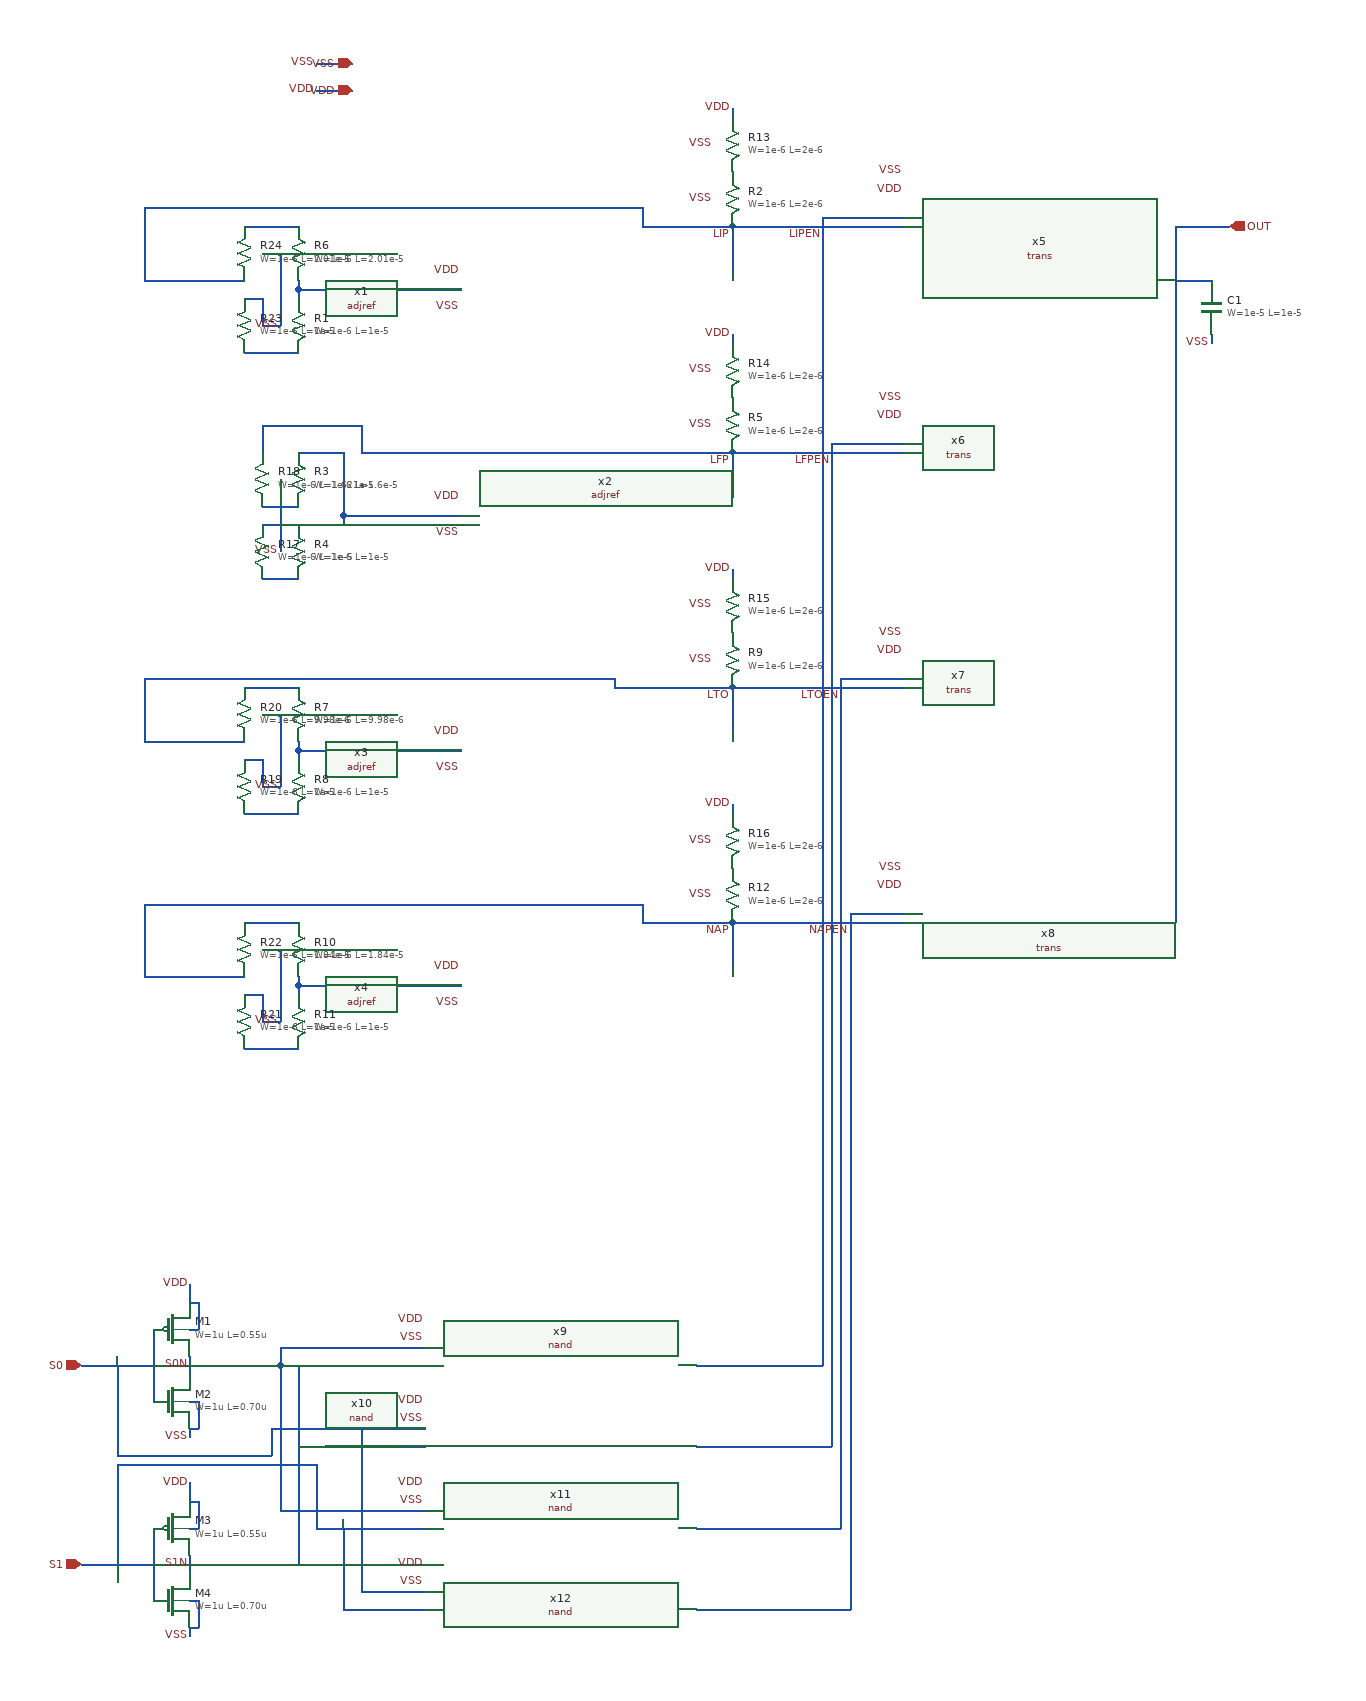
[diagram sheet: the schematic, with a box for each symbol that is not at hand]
v {xschem version=3.4.8RC file_version=1.3}
G {}
K {}
V {}
S {}
F {}
E {}
N -250 -250 -210 -250 {lab=VSS}
N -250 -220 -210 -220 {lab=VDD}
N -270 -0 -90 0 {lab=#net1}
N -270 -10 -270 -0 {lab=#net1}
N -270 0 -270 10 {lab=#net1}
N -290 70 -270 70 {lab=#net2}
N 210 180 210 230 {lab=LFP}
N -270 510 -90 510 {lab=#net3}
N -270 500 -270 510 {lab=#net3}
N -270 510 -270 520 {lab=#net3}
N -290 580 -270 580 {lab=#net4}
N 210 440 210 490 {lab=LTO}
N -270 770 -90 770 {lab=#net5}
N -270 760 -270 770 {lab=#net5}
N -270 770 -270 780 {lab=#net5}
N -290 840 -270 840 {lab=#net6}
N 210 700 210 750 {lab=NAP}
N 210 -70 400 -70 {lab=LIP}
N 210 -70 210 -20 {lab=LIP}
N 210 180 400 180 {lab=LFP}
N 210 440 400 440 {lab=LTO}
N 700 -70 760 -70 {lab=OUT}
N 700 -70 700 700 {lab=OUT}
N -390 1230 -380 1230 {lab=VSS}
N -380 1230 -380 1260 {lab=VSS}
N -390 1260 -380 1260 {lab=VSS}
N -390 1260 -390 1270 {lab=VSS}
N -390 1150 -380 1150 {lab=VDD}
N -380 1120 -380 1150 {lab=VDD}
N -390 1120 -380 1120 {lab=VDD}
N -390 1100 -390 1120 {lab=VDD}
N -390 1180 -390 1200 {lab=S0N}
N -430 1150 -430 1230 {lab=S0}
N -390 1450 -380 1450 {lab=VSS}
N -380 1450 -380 1480 {lab=VSS}
N -390 1480 -380 1480 {lab=VSS}
N -390 1480 -390 1490 {lab=VSS}
N -390 1370 -380 1370 {lab=VDD}
N -380 1340 -380 1370 {lab=VDD}
N -390 1340 -380 1340 {lab=VDD}
N -390 1320 -390 1340 {lab=VDD}
N -390 1400 -390 1420 {lab=S1N}
N -430 1370 -430 1450 {lab=S1}
N -510 1190 -430 1190 {lab=S0}
N -510 1410 -430 1410 {lab=S1}
N 700 -10 740 -10 {lab=OUT}
N 740 50 740 60 {lab=VSS}
N -290 1170 -130 1170 {lab=S0N}
N -290 1170 -290 1190 {lab=S0N}
N -390 1190 -290 1190 {lab=S0N}
N -270 1190 -130 1190 {lab=S1N}
N -270 1190 -270 1410 {lab=S1N}
N -390 1410 -270 1410 {lab=S1N}
N -300 1260 -130 1260 {lab=S0}
N -300 1260 -300 1290 {lab=S0}
N -470 1290 -300 1290 {lab=S0}
N -470 1190 -470 1290 {lab=S0}
N -270 1280 -130 1280 {lab=S1N}
N -250 1370 -130 1370 {lab=S1}
N -250 1300 -250 1370 {lab=S1}
N -470 1300 -250 1300 {lab=S1}
N -470 1300 -470 1410 {lab=S1}
N -290 1350 -130 1350 {lab=S0N}
N -290 1190 -290 1350 {lab=S0N}
N -200 1440 -130 1440 {lab=S0}
N -200 1260 -200 1440 {lab=S0}
N -220 1460 -130 1460 {lab=S1}
N -220 1370 -220 1460 {lab=S1}
N 310 -80 400 -80 {lab=LIPEN}
N 310 -80 310 1190 {lab=LIPEN}
N 170 1190 310 1190 {lab=LIPEN}
N 320 170 400 170 {lab=LFPEN}
N 320 170 320 1280 {lab=LFPEN}
N 170 1280 320 1280 {lab=LFPEN}
N 330 430 400 430 {lab=LTOEN}
N 330 430 330 1370 {lab=LTOEN}
N 170 1370 330 1370 {lab=LTOEN}
N 340 690 400 690 {lab=NAPEN}
N 340 690 340 1460 {lab=NAPEN}
N 170 1460 340 1460 {lab=NAPEN}
N 210 700 400 700 {lab=NAP}
N 210 50 210 60 {lab=VDD}
N 210 -200 210 -190 {lab=VDD}
N 210 310 210 320 {lab=VDD}
N 210 570 210 580 {lab=VDD}
N -310 320 -270 320 {lab=#net7}
N -290 210 -290 290 {lab=VSS}
N -200 180 210 180 {lab=LFP}
N -200 150 -200 180 {lab=LFP}
N -310 150 -200 150 {lab=LFP}
N -310 150 -310 180 {lab=LFP}
N -310 240 -270 240 {lab=#net8}
N -270 180 -220 180 {lab=#net9}
N -220 180 -220 250 {lab=#net9}
N -220 250 -90 250 {lab=#net9}
N -310 260 -290 260 {lab=VSS}
N -270 260 -220 260 {lab=#net9}
N -220 250 -220 260 {lab=#net9}
N -330 520 -310 520 {lab=VSS}
N -310 520 -310 550 {lab=VSS}
N -310 550 -290 550 {lab=VSS}
N -330 580 -290 580 {lab=#net4}
N -290 470 -290 550 {lab=VSS}
N -310 470 -290 470 {lab=VSS}
N -330 440 -270 440 {lab=#net10}
N -440 500 -330 500 {lab=LTO}
N -440 430 -440 500 {lab=LTO}
N -440 430 80 430 {lab=LTO}
N 80 430 80 440 {lab=LTO}
N 80 440 210 440 {lab=LTO}
N -310 810 -290 810 {lab=VSS}
N -330 840 -290 840 {lab=#net6}
N -290 730 -290 810 {lab=VSS}
N -310 730 -290 730 {lab=VSS}
N -330 780 -310 780 {lab=VSS}
N -310 780 -310 810 {lab=VSS}
N -330 700 -270 700 {lab=#net11}
N -440 760 -330 760 {lab=NAP}
N -440 680 -440 760 {lab=NAP}
N -440 680 110 680 {lab=NAP}
N 110 680 110 700 {lab=NAP}
N 110 700 210 700 {lab=NAP}
N -330 70 -290 70 {lab=#net2}
N -330 10 -310 10 {lab=VSS}
N -310 10 -310 40 {lab=VSS}
N -310 40 -290 40 {lab=VSS}
N -290 -40 -290 40 {lab=VSS}
N -310 -40 -290 -40 {lab=VSS}
N -330 -70 -270 -70 {lab=#net12}
N -440 -10 -330 -10 {lab=LIP}
N -440 -90 -440 -10 {lab=LIP}
N -440 -90 110 -90 {lab=LIP}
N 110 -90 110 -70 {lab=LIP}
N 110 -70 210 -70 {lab=LIP}
C {adjref.sym} 60 0 0 0 {name=x1}
C {symbols/ppolyf_u_1k_6p0.sym} -270 -40 0 0 {name=R6
W=1e-6
L=2.01e-5
model=ppolyf_u_1k
spiceprefix=X
m=1}
C {lab_pin.sym} -250 -250 0 0 {name=p26 sig_type=std_logic lab=VSS}
C {iopin.sym} -210 -250 0 0 {name=p27 lab=VSS}
C {lab_pin.sym} -250 -220 0 0 {name=p30 sig_type=std_logic lab=VDD}
C {iopin.sym} -210 -220 0 0 {name=p31 lab=VDD}
C {lab_pin.sym} -90 20 0 0 {name=p1 sig_type=std_logic lab=VSS}
C {lab_pin.sym} -90 -20 0 0 {name=p2 sig_type=std_logic lab=VDD}
C {symbols/ppolyf_u_1k_6p0.sym} -270 40 0 0 {name=R1
W=1e-6
L=1e-5
model=ppolyf_u_1k
spiceprefix=X
m=1}
C {lab_pin.sym} -290 40 1 0 {name=p3 sig_type=std_logic lab=VSS}
C {symbols/ppolyf_u_1k_6p0.sym} 210 -100 0 0 {name=R2
W=1e-6
L=2e-6
model=ppolyf_u_1k
spiceprefix=X
m=1}
C {lab_pin.sym} 190 -100 0 0 {name=p4 sig_type=std_logic lab=VSS}
C {adjref.sym} 60 250 0 0 {name=x2}
C {symbols/ppolyf_u_1k_6p0.sym} -270 210 0 0 {name=R3
W=1e-6
L=1.6e-5
model=ppolyf_u_1k
spiceprefix=X
m=1}
C {lab_pin.sym} -90 270 0 0 {name=p9 sig_type=std_logic lab=VSS}
C {lab_pin.sym} -90 230 0 0 {name=p10 sig_type=std_logic lab=VDD}
C {symbols/ppolyf_u_1k_6p0.sym} -270 290 0 0 {name=R4
W=1e-6
L=1e-5
model=ppolyf_u_1k
spiceprefix=X
m=1}
C {lab_pin.sym} -290 290 1 0 {name=p11 sig_type=std_logic lab=VSS}
C {symbols/ppolyf_u_1k_6p0.sym} 210 150 0 0 {name=R5
W=1e-6
L=2e-6
model=ppolyf_u_1k
spiceprefix=X
m=1}
C {lab_pin.sym} 190 150 0 0 {name=p12 sig_type=std_logic lab=VSS}
C {lab_pin.sym} 210 -60 0 0 {name=p6 sig_type=std_logic lab=LIP}
C {lab_pin.sym} 210 190 0 0 {name=p14 sig_type=std_logic lab=LFP}
C {adjref.sym} 60 510 0 0 {name=x3}
C {symbols/ppolyf_u_1k_6p0.sym} -270 470 0 0 {name=R7
W=1e-6
L=9.98e-6
model=ppolyf_u_1k
spiceprefix=X
m=1}
C {lab_pin.sym} -90 530 0 0 {name=p16 sig_type=std_logic lab=VSS}
C {lab_pin.sym} -90 490 0 0 {name=p17 sig_type=std_logic lab=VDD}
C {symbols/ppolyf_u_1k_6p0.sym} -270 550 0 0 {name=R8
W=1e-6
L=1e-5
model=ppolyf_u_1k
spiceprefix=X
m=1}
C {lab_pin.sym} -290 550 1 0 {name=p18 sig_type=std_logic lab=VSS}
C {symbols/ppolyf_u_1k_6p0.sym} 210 410 0 0 {name=R9
W=1e-6
L=2e-6
model=ppolyf_u_1k
spiceprefix=X
m=1}
C {lab_pin.sym} 190 410 0 0 {name=p19 sig_type=std_logic lab=VSS}
C {lab_pin.sym} 210 450 0 0 {name=p21 sig_type=std_logic lab=LTO}
C {adjref.sym} 60 770 0 0 {name=x4}
C {symbols/ppolyf_u_1k_6p0.sym} -270 730 0 0 {name=R10
W=1e-6
L=1.84e-5
model=ppolyf_u_1k
spiceprefix=X
m=1}
C {lab_pin.sym} -90 790 0 0 {name=p23 sig_type=std_logic lab=VSS}
C {lab_pin.sym} -90 750 0 0 {name=p24 sig_type=std_logic lab=VDD}
C {symbols/ppolyf_u_1k_6p0.sym} -270 810 0 0 {name=R11
W=1e-6
L=1e-5
model=ppolyf_u_1k
spiceprefix=X
m=1}
C {lab_pin.sym} -290 810 1 0 {name=p25 sig_type=std_logic lab=VSS}
C {symbols/ppolyf_u_1k_6p0.sym} 210 670 0 0 {name=R12
W=1e-6
L=2e-6
model=ppolyf_u_1k
spiceprefix=X
m=1}
C {lab_pin.sym} 190 670 0 0 {name=p28 sig_type=std_logic lab=VSS}
C {lab_pin.sym} 210 710 0 0 {name=p32 sig_type=std_logic lab=NAP}
C {trans.sym} 550 -100 0 0 {name=x5}
C {lab_pin.sym} 400 -130 0 0 {name=p33 sig_type=std_logic lab=VSS}
C {lab_pin.sym} 400 -110 0 0 {name=p34 sig_type=std_logic lab=VDD}
C {trans.sym} 550 150 0 0 {name=x6}
C {lab_pin.sym} 400 120 0 0 {name=p35 sig_type=std_logic lab=VSS}
C {lab_pin.sym} 400 140 0 0 {name=p36 sig_type=std_logic lab=VDD}
C {trans.sym} 550 410 0 0 {name=x7}
C {lab_pin.sym} 400 380 0 0 {name=p37 sig_type=std_logic lab=VSS}
C {lab_pin.sym} 400 400 0 0 {name=p38 sig_type=std_logic lab=VDD}
C {trans.sym} 550 670 0 0 {name=x8}
C {lab_pin.sym} 400 640 0 0 {name=p39 sig_type=std_logic lab=VSS}
C {lab_pin.sym} 400 660 0 0 {name=p40 sig_type=std_logic lab=VDD}
C {opin.sym} 760 -70 0 0 {name=p41 lab=OUT}
C {symbols/pfet_06v0.sym} -410 1150 0 0 {name=M1
L=0.55u
W=1u
nf=1
m=1
ad="'int((nf+1)/2) * W/nf * 0.18u'"
pd="'2*int((nf+1)/2) * (W/nf + 0.18u)'"
as="'int((nf+2)/2) * W/nf * 0.18u'"
ps="'2*int((nf+2)/2) * (W/nf + 0.18u)'"
nrd="'0.18u / W'" nrs="'0.18u / W'"
sa=0 sb=0 sd=0
model=pfet_06v0
spiceprefix=X
}
C {symbols/nfet_06v0.sym} -410 1230 0 0 {name=M2
L=0.70u
W=1u
nf=1
m=1
ad="'int((nf+1)/2) * W/nf * 0.18u'"
pd="'2*int((nf+1)/2) * (W/nf + 0.18u)'"
as="'int((nf+2)/2) * W/nf * 0.18u'"
ps="'2*int((nf+2)/2) * (W/nf + 0.18u)'"
nrd="'0.18u / W'" nrs="'0.18u / W'"
sa=0 sb=0 sd=0
model=nfet_06v0
spiceprefix=X
}
C {lab_pin.sym} -390 1270 0 0 {name=p42 sig_type=std_logic lab=VSS}
C {lab_pin.sym} -390 1100 0 0 {name=p43 sig_type=std_logic lab=VDD}
C {symbols/pfet_06v0.sym} -410 1370 0 0 {name=M3
L=0.55u
W=1u
nf=1
m=1
ad="'int((nf+1)/2) * W/nf * 0.18u'"
pd="'2*int((nf+1)/2) * (W/nf + 0.18u)'"
as="'int((nf+2)/2) * W/nf * 0.18u'"
ps="'2*int((nf+2)/2) * (W/nf + 0.18u)'"
nrd="'0.18u / W'" nrs="'0.18u / W'"
sa=0 sb=0 sd=0
model=pfet_06v0
spiceprefix=X
}
C {symbols/nfet_06v0.sym} -410 1450 0 0 {name=M4
L=0.70u
W=1u
nf=1
m=1
ad="'int((nf+1)/2) * W/nf * 0.18u'"
pd="'2*int((nf+1)/2) * (W/nf + 0.18u)'"
as="'int((nf+2)/2) * W/nf * 0.18u'"
ps="'2*int((nf+2)/2) * (W/nf + 0.18u)'"
nrd="'0.18u / W'" nrs="'0.18u / W'"
sa=0 sb=0 sd=0
model=nfet_06v0
spiceprefix=X
}
C {lab_pin.sym} -390 1490 0 0 {name=p44 sig_type=std_logic lab=VSS}
C {lab_pin.sym} -390 1320 0 0 {name=p45 sig_type=std_logic lab=VDD}
C {ipin.sym} -510 1190 0 0 {name=p46 lab=S0}
C {ipin.sym} -510 1410 0 0 {name=p47 lab=S1}
C {nand.sym} 20 1170 0 0 {name=x9}
C {nand.sym} 20 1260 0 0 {name=x10}
C {nand.sym} 20 1350 0 0 {name=x11}
C {nand.sym} 20 1440 0 0 {name=x12}
C {lab_pin.sym} 740 60 3 0 {name=p48 sig_type=std_logic lab=VSS}
C {lab_pin.sym} -130 1140 0 0 {name=p49 sig_type=std_logic lab=VDD}
C {lab_pin.sym} -130 1230 0 0 {name=p50 sig_type=std_logic lab=VDD}
C {lab_pin.sym} -130 1320 0 0 {name=p51 sig_type=std_logic lab=VDD}
C {lab_pin.sym} -130 1410 0 0 {name=p52 sig_type=std_logic lab=VDD}
C {lab_pin.sym} -130 1160 0 0 {name=p53 sig_type=std_logic lab=VSS}
C {lab_pin.sym} -130 1250 0 0 {name=p54 sig_type=std_logic lab=VSS}
C {lab_pin.sym} -130 1340 0 0 {name=p55 sig_type=std_logic lab=VSS}
C {lab_pin.sym} -130 1430 0 0 {name=p56 sig_type=std_logic lab=VSS}
C {lab_pin.sym} -390 1190 0 0 {name=p57 sig_type=std_logic lab=S0N}
C {lab_pin.sym} -390 1410 0 0 {name=p58 sig_type=std_logic lab=S1N}
C {lab_pin.sym} 310 -60 0 0 {name=p59 sig_type=std_logic lab=LIPEN}
C {lab_pin.sym} 320 190 0 0 {name=p60 sig_type=std_logic lab=LFPEN}
C {lab_pin.sym} 330 450 0 0 {name=p61 sig_type=std_logic lab=LTOEN}
C {lab_pin.sym} 340 710 0 0 {name=p62 sig_type=std_logic lab=NAPEN}
C {symbols/cap_mim_2f0fF.sym} 740 20 0 0 {name=C1
W=1e-5
L=1e-5
model=cap_mim_2f0fF
spiceprefix=X
m=1}
C {lab_pin.sym} 210 -200 0 0 {name=p5 sig_type=std_logic lab=VDD}
C {lab_pin.sym} 210 50 0 0 {name=p13 sig_type=std_logic lab=VDD}
C {lab_pin.sym} 210 310 0 0 {name=p20 sig_type=std_logic lab=VDD}
C {lab_pin.sym} 210 570 0 0 {name=p29 sig_type=std_logic lab=VDD}
C {symbols/ppolyf_u_1k_6p0.sym} 210 -160 0 0 {name=R13
W=1e-6
L=2e-6
model=ppolyf_u_1k
spiceprefix=X
m=1}
C {lab_pin.sym} 190 -160 0 0 {name=p63 sig_type=std_logic lab=VSS}
C {symbols/ppolyf_u_1k_6p0.sym} 210 90 0 0 {name=R14
W=1e-6
L=2e-6
model=ppolyf_u_1k
spiceprefix=X
m=1}
C {lab_pin.sym} 190 90 0 0 {name=p64 sig_type=std_logic lab=VSS}
C {symbols/ppolyf_u_1k_6p0.sym} 210 350 0 0 {name=R15
W=1e-6
L=2e-6
model=ppolyf_u_1k
spiceprefix=X
m=1}
C {lab_pin.sym} 190 350 0 0 {name=p65 sig_type=std_logic lab=VSS}
C {symbols/ppolyf_u_1k_6p0.sym} 210 610 0 0 {name=R16
W=1e-6
L=2e-6
model=ppolyf_u_1k
spiceprefix=X
m=1}
C {lab_pin.sym} 190 610 0 0 {name=p66 sig_type=std_logic lab=VSS}
C {symbols/ppolyf_u_1k_6p0.sym} -310 290 0 1 {name=R17
W=1e-6
L=1e-5
model=ppolyf_u_1k
spiceprefix=X
m=1}
C {symbols/ppolyf_u_1k_6p0.sym} -310 210 0 1 {name=R18
W=1e-6
L=1.621e-5
model=ppolyf_u_1k
spiceprefix=X
m=1}
C {symbols/ppolyf_u_1k_6p0.sym} -330 550 2 0 {name=R19
W=1e-6
L=1e-5
model=ppolyf_u_1k
spiceprefix=X
m=1}
C {symbols/ppolyf_u_1k_6p0.sym} -330 470 2 0 {name=R20
W=1e-6
L=9.98e-6
model=ppolyf_u_1k
spiceprefix=X
m=1}
C {symbols/ppolyf_u_1k_6p0.sym} -330 810 2 0 {name=R21
W=1e-6
L=1e-5
model=ppolyf_u_1k
spiceprefix=X
m=1}
C {symbols/ppolyf_u_1k_6p0.sym} -330 730 2 0 {name=R22
W=1e-6
L=1.84e-5
model=ppolyf_u_1k
spiceprefix=X
m=1}
C {symbols/ppolyf_u_1k_6p0.sym} -330 40 2 0 {name=R23
W=1e-6
L=1e-5
model=ppolyf_u_1k
spiceprefix=X
m=1}
C {symbols/ppolyf_u_1k_6p0.sym} -330 -40 2 0 {name=R24
W=1e-6
L=2.01e-5
model=ppolyf_u_1k
spiceprefix=X
m=1}
